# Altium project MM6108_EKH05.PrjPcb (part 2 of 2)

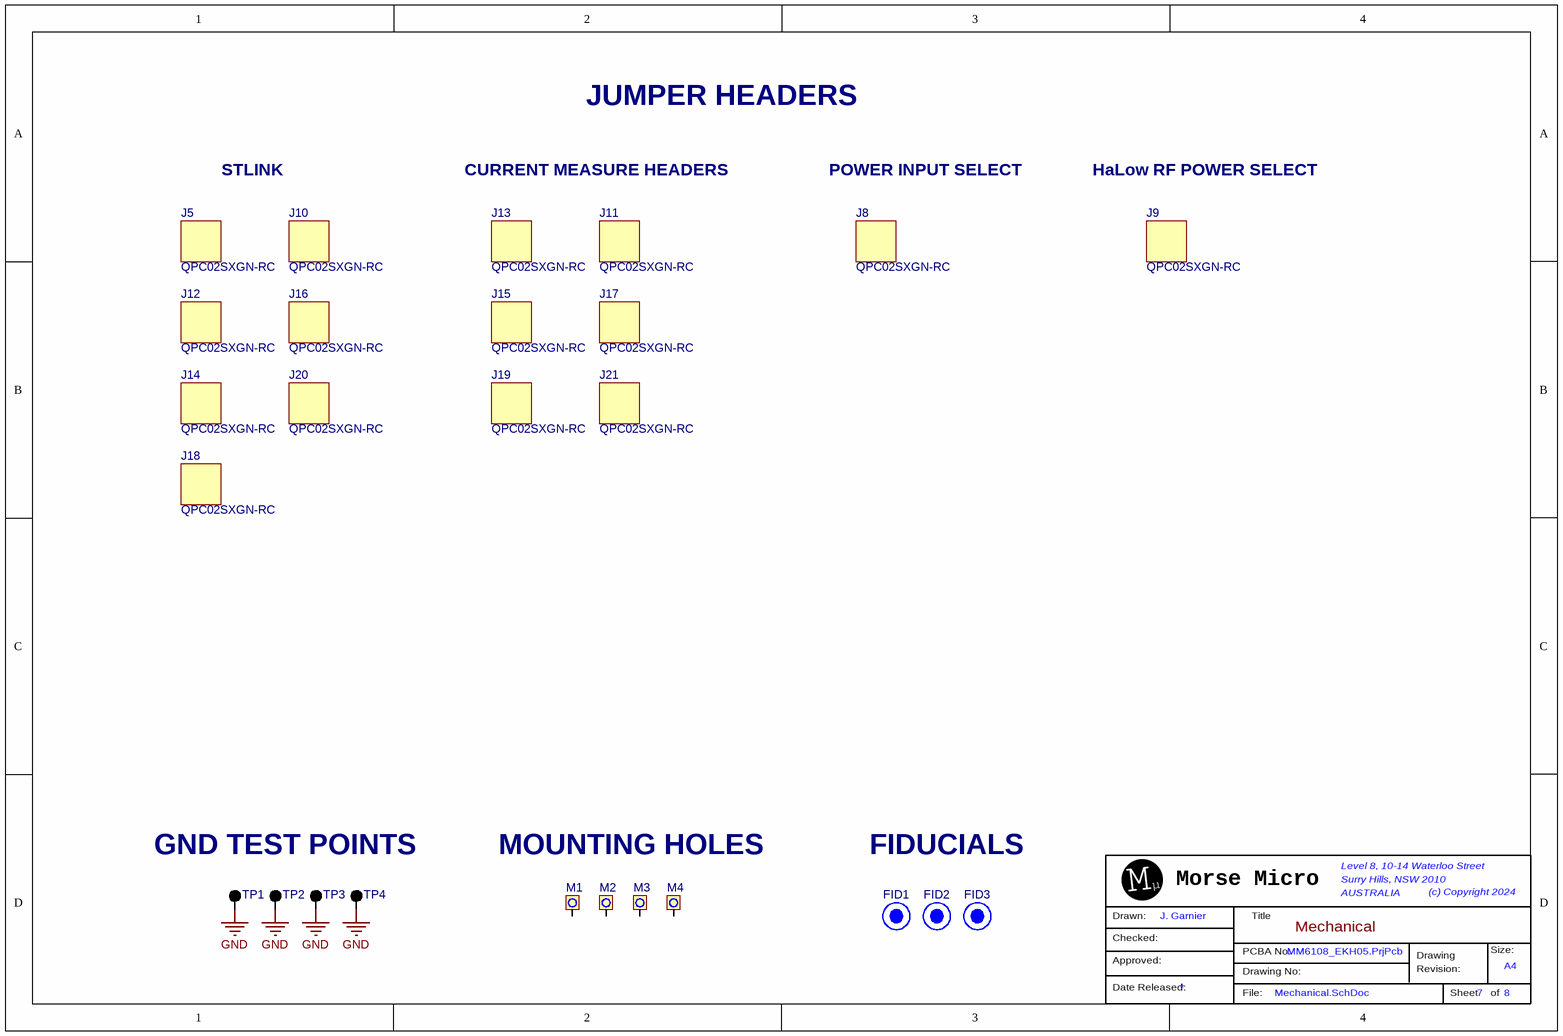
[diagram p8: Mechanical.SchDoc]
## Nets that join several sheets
+5V: Power (8 pins), Sensors (R60.2)
GND: Power (39 pins), STM_MCU (46 pins), Sensors (32 pins), BLE_Module (6 pins), HaLow_Module (34 pins), Mechanical (TP1.1 TP2.1 TP3.1 TP4.1)
MM_VBAT: Power (H19.2), HaLow_Module (C29.1 C30.1 R46.1 U2.25)
MM_VDDIO: Power (H22.2), HaLow_Module (9 pins)
MM_VFEM: Power (H26.2 R35.1), HaLow_Module (L2.2)
VDD_MCU: Power (H24.2), STM_MCU (30 pins)
VDD_SENSORS: Power (H25.2), STM_MCU (C24.2 R82.1 R85.1 U1.8), Sensors (5 pins), BLE_Module (R47.1 R48.1 R50.1)
ACC_INT1: STM_MCU (IC1.28), Sensors (U3.7)
ACC_INT2: STM_MCU (IC1.29), Sensors (U3.3)
BLE_RESET_N: STM_MCU (IC1.83), BLE_Module (C35.2 IC2.19 R50.2)
BLE_SPI_CS: STM_MCU (IC1.77), BLE_Module (H7.4 IC2.11)
BLE_SPI_IRQ: STM_MCU (IC1.23), BLE_Module (H7.5 IC2.7 R48.2 R49.1)
BLE_SPI_MISO: STM_MCU (IC1.79), BLE_Module (H7.3 IC2.16)
BLE_SPI_MOSI: STM_MCU (IC1.80), BLE_Module (H7.2 IC2.17)
BLE_SPI_SCK: STM_MCU (IC1.78), BLE_Module (H7.1 IC2.15)
CAM_PWDN: STM_MCU (IC1.2), Sensors (H13.18)
CAM_RESET: STM_MCU (IC1.1), Sensors (H13.17)
CAM_XCLK: STM_MCU (IC1.67), Sensors (H13.8)
DBG_UART_STM_RX: Power (H16.11), STM_MCU (H2.2 IC1.15)
DBG_UART_STM_TX: Power (H16.13), STM_MCU (H2.1 IC1.16)
DCMI_D0: STM_MCU (IC1.63), Sensors (H13.16)
DCMI_D1: STM_MCU (IC1.64), Sensors (H13.15)
DCMI_D2: STM_MCU (IC1.65), Sensors (H13.14)
DCMI_D3: STM_MCU (IC1.66), Sensors (H13.13)
DCMI_D4: STM_MCU (IC1.3), Sensors (H13.12)
DCMI_D5: STM_MCU (IC1.92), Sensors (H13.11)
DCMI_D6: STM_MCU (IC1.4), Sensors (H13.10)
DCMI_D7: STM_MCU (IC1.5), Sensors (H13.9)
DCMI_HSYNC: STM_MCU (IC1.55), Sensors (H13.6)
DCMI_PIXCLK: STM_MCU (IC1.56), Sensors (H13.7)
DCMI_VSYNC: STM_MCU (IC1.93), Sensors (H13.5)
I2C_SCL: STM_MCU (IC1.95 R82.2), Sensors (6 pins)
I2C_SDA: STM_MCU (IC1.96 R85.2), Sensors (6 pins)
MIKRO_AN: STM_MCU (IC1.34), Sensors (J1.1)
MIKRO_INT: STM_MCU (IC1.37), Sensors (J2.2)
MIKRO_PWM: STM_MCU (IC1.38), Sensors (J2.1)
MIKRO_RST: STM_MCU (IC1.52), Sensors (J1.2)
MM_BUSY: STM_MCU (IC1.91), HaLow_Module (R11.2 U2.34)
MM_RESET_N: STM_MCU (IC1.97), HaLow_Module (C32.1 H5.8 R46.2 U2.35)
MM_SDIO_D1: STM_MCU (IC1.54), HaLow_Module (R23.2 U2.16)
MM_SDIO_D2: STM_MCU (IC1.89 R3.2), HaLow_Module (R22.2 U2.23)
MM_SDIO_D3: STM_MCU (IC1.90), HaLow_Module (H5.14 R21.2 U2.22)
MM_WAKE: STM_MCU (IC1.81), HaLow_Module (H5.16 U2.36)
NetH16_5: Power (H16.5), STM_MCU (R3.1)
PD11: STM_MCU (IC1.58), Sensors (C36.1 R51.2)
SDMMC2_CLK: STM_MCU (IC1.87), HaLow_Module (R31.1)
SDMMC2_CMD: STM_MCU (IC1.88), HaLow_Module (R32.1)
SDMMC2_D0: STM_MCU (IC1.53), HaLow_Module (R33.1)
SENSORS_SPI_CLK: STM_MCU (IC1.41), Sensors (H9.1 J1.4)
SENSORS_SPI_CS: STM_MCU (IC1.40), Sensors (H9.4 J1.3)
SENSORS_SPI_MISO: STM_MCU (IC1.42), Sensors (H9.2 J1.5)
SENSORS_SPI_MOSI: STM_MCU (IC1.43), Sensors (H9.3 J1.6)
SENSORS_UART_RX: STM_MCU (IC1.44), Sensors (H8.1 J2.3)
SENSORS_UART_TX: STM_MCU (IC1.45), Sensors (H8.2 J2.4)
STM_NRST: Power (H16.9), STM_MCU (5 pins)
STM_SPI2_CLK: STM_MCU (IC1.82), HaLow_Module (R41.2)
STM_SPI2_MISO: STM_MCU (IC1.84), HaLow_Module (R43.2)
STM_SPI2_MOSI: STM_MCU (IC1.85), HaLow_Module (R42.2)
SWD_CLK: Power (H16.3), STM_MCU (IC1.76)
SWD_DIO: Power (H16.7), STM_MCU (IC1.72)
TIM4_CH1: STM_MCU (IC1.59), Sensors (R64.1 R67.2)
TIM4_CH2: STM_MCU (IC1.60), Sensors (R63.1 R66.2)
TIM4_CH3: STM_MCU (IC1.61), Sensors (R62.1 R65.2)
USBC_N: Power (D12.K J3.A7 J3.B7), STM_MCU (IC1.70)
USBC_P: Power (D11.K J3.A6 J3.B6), STM_MCU (IC1.71)
VFEM_ADC: Power (R35.2 R36.1), STM_MCU (IC1.17)
VFEM_SHUNT_TOGGLE: Power (R36.2), STM_MCU (IC1.86)

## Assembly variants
Default: not fitted D7 D8 D9 D10 H5 R3 R7 R25 R26 R31 R32 R33 R46 R48 R50 R78 R79 R80 R81 R83 R? U5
